! (c) 2009  Infineon Technologies AG, Munich
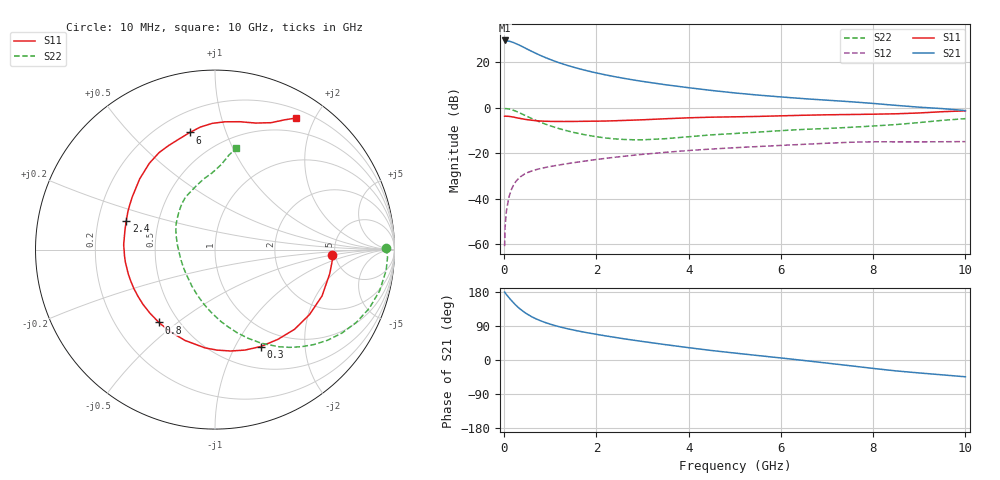
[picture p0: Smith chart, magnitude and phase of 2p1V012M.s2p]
! Infineon Technologies  Discrete & RF Semiconductors
! BFP420
! VCE =  1.0 V,  IC =  12 mA
! Common Emitter S-Parameters:  Nov 2009
# GHz  S  MA  R  50
!  f  S11  S21  S12  S22
! GHz  MAG  ANG  MAG  ANG  MAG  ANG  MAG  ANG
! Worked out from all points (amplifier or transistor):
!   46 points, 10 MHz to 10 GHz, reference 50 ohm
!   highest |S21| = 29.7 dB at 10 MHz (marker M1)
!   |S21| within 3 dB of that: start of sweep to 421.8 MHz
!   unconditionally stable (mu >= 1): 2.125 GHz to end of sweep
!   at 300 MHz: K = 0.22, MSG = 29.6 dB, |S12| = -31.3 dB
!   at 1.7 GHz: K = 0.89, MSG = 20.2 dB, |S12| = -23.6 dB
!   at 10 GHz: K = 1.07, MAG = 5.2 dB, |S12| = -14.9 dB
!   lowest NFmin = 0.95 dB at 900 MHz
!   S11 on the Smith chart (normalised r, x): 10 MHz: 4.74, -0.51; 300 MHz: 0.76, -1.28; 800 MHz: 0.39, -0.43; 2.4 GHz: 0.32, +0.14; 6 GHz: 0.32, +0.76; 10 GHz: 0.31, +1.75
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0.01  0.6549 -2.7  30.51 179.3  0.0009 103.5  0.9544 0.5
0.02  0.6567 -4.9  29.9 177.3  0.0023 90.4  0.9622 -2.6
0.1  0.65 -23.4  29.49 165.2  0.0105 79.9  0.9456 -14.0
0.15  0.639 -34.5  28.61 158.1  0.0153 75.1  0.9194 -20.9
0.2  0.6273 -45.1  27.5 151.5  0.0197 70.6  0.8854 -27.3
0.25  0.6106 -55.0  26.14 145.1  0.0236 66.6  0.8472 -33.2
0.3  0.5972 -64.7  24.85 139.4  0.0271 63.0  0.8058 -38.8
0.4  0.5716 -81.3  22.17 129.5  0.0328 57.2  0.7237 -48.4
0.5  0.5504 -95.8  19.68 121.1  0.0373 52.8  0.6477 -56.7
0.6  0.5331 -108.2  17.51 114.0  0.0408 49.6  0.5817 -63.7
0.7  0.5211 -118.7  15.65 108.1  0.0438 47.3  0.5252 -69.8
0.8  0.5123 -127.6  14.07 103.0  0.0464 45.7  0.4774 -75.3
1  0.5041 -142.7  11.62 94.5  0.0511 43.5  0.4023 -85.2
1.2  0.5014 -154.4  9.8 87.6  0.0554 42.3  0.347 -94.1
1.7  0.5054 -176.2  6.955 74.3  0.0663 40.3  0.2616 -114.4
2.4  0.5196 162.1  4.858 59.8  0.0817 37.0  0.2074 -143.0
3.5  0.5756 136.8  3.229 40.5  0.105 29.7  0.2097 174.1
5.5  0.6479 108.0  1.914 11.8  0.1406 14.0  0.2924 133.2
6  0.6676 102.1  1.741 5.4  0.149 10.1  0.3151 126.0
7  0.7036 91.2  1.475 -8.2  0.1665 1.1  0.3517 112.2
8.5  0.7405 72.2  1.134 -28.8  0.1786 -15.2  0.4292 91.9
10  0.8604 58.4  0.872 -44.3  0.1807 -25.7  0.579 78.1
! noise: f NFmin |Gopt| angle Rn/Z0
0.9  0.95  0.03  -151  0.13
1.8  1.27  0.13  -152  0.12
2.4  1.38  0.13  -160  0.14
3  1.43  0.22  -145  0.13
4  1.58  0.35  -123  0.17
5  2.03  0.43  -103  0.28
6  2.4  0.47  -91  0.43
